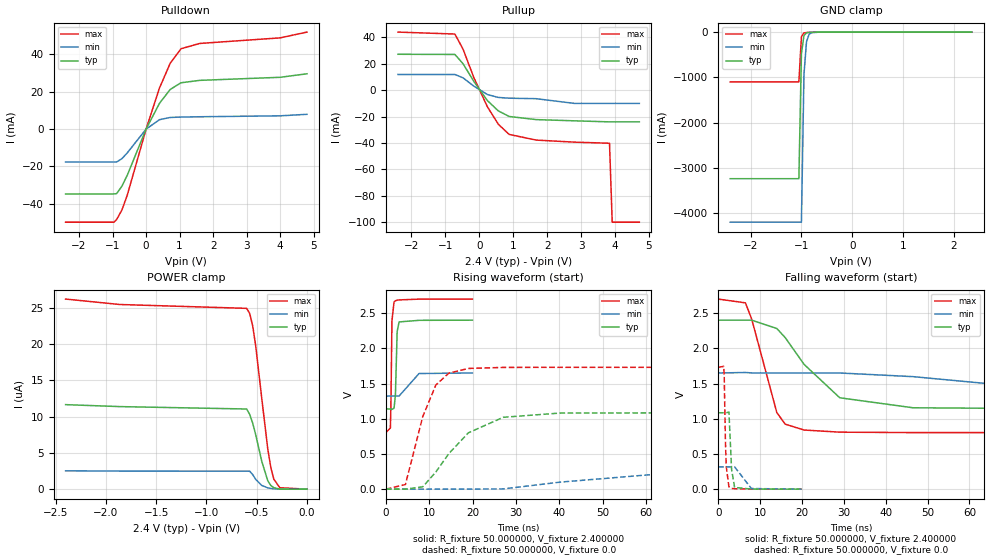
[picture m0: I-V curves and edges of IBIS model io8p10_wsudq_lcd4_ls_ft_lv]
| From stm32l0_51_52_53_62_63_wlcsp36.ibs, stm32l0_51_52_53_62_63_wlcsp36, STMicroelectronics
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|   Model io8p10_wsudq_lcd4_ls_ft_lv
[Model]  io8p10_wsudq_lcd4_ls_ft_lv
Model_type I/O
Polarity   Non-Inverting
Enable   Active-Low
Vinl =   0.720000V
Vinh =   1.680000V
Vmeas =  1.200000V
Cref =   50.000000pF
Rref =   100.000000M
Vref =   0.0V
C_comp   3.178800pF   3.170000pF   3.206700pF
[Temperature Range]   25.000000   0.105000k   -40.000000
[Pullup Reference]   2.400000V   1.650000V   2.700000V
[Pulldown Reference]   0.0V   0.0V   0.0V
[POWER Clamp Reference]   2.400000V   1.650000V   2.700000V
[GND Clamp Reference]   0.0V   0.0V   0.0V
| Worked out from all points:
|   slope of the pulldown table from 0 to 0.36 V, typ, clamps not added: 28.5 ohm
|   slope of the pullup table from 0 to 0.36 V, typ, clamps not added: 32.2 ohm
|   GND clamp passes 1 mA (typ) near -0.64 V on its own axis
|   rising waveform, R_fixture 50.000000, V_fixture 2.400000: 20-80 % time 297ps typ, 642ps min, 211ps max; typ from 1.14 V to 2.4 V
|   rising waveform, R_fixture 50.000000, V_fixture 0.0: 20-80 % time 9.37ns typ, 24.7ns min, 4.83ns max; typ from 0 V to 1.08 V
|   falling waveform, R_fixture 50.000000, V_fixture 2.400000: 20-80 % time 10ns typ, 27ns min, 4.94ns max; typ from 2.4 V to 1.14 V
|   falling waveform, R_fixture 50.000000, V_fixture 0.0: 20-80 % time 491ps typ, 860ps min, 390ps max; typ from 1.08 V to 0 V
[Pulldown]
|Voltage   I(typ)   I(min)   I(max)
-2.4V     -34.7mA    -17.61mA   -49.82mA
-960mV    -34.7mA    -17.61mA   -49.82mA
-880mV    -34.55mA   -17.61mA   -48.46mA
-720mV    -30.52mA   -15.79mA   -43.28mA
-560mV    -24.65mA   -12.68mA   -35.33mA
0V        326fA      0A         140fA
400mV     13.84mA    5.066mA    22.03mA
720mV     21.25mA    6.254mA    35.26mA
1.04V     24.82mA    6.464mA    43.03mA
1.6V      26.11mA    6.627mA    45.88mA
4V        27.76mA    7.125mA    48.87mA
4.8V      29.64mA    7.94mA     51.96mA
[Pullup]
|Voltage   I(typ)   I(min)   I(max)
-2.4V     27.21mA    11.89mA    44.01mA
-720mV    27.06mA    11.89mA    42.53mA
-480mV    20.06mA    9.352mA    31.11mA
-160mV    6.586mA    3.048mA    9.467mA
240mV     -7.917mA   -3.299mA   -12.65mA
560mV     -15.67mA   -5.497mA   -25.76mA
880mV     -19.92mA   -6.062mA   -33.51mA
1.68V     -22.29mA   -6.449mA   -37.81mA
2.8V      -23.2mA    -10mA      -39.35mA
3.84V     -24mA      -10mA      -40.2mA
3.92V     -24mA      -10mA      -100mA
4.72V     -24mA      -10mA      -100mA
[GND_clamp]
|Voltage   I(typ)   I(min)   I(max)
-2.4V     -3.238A    -4.199A    -1.101A
-1.05V    -3.238A    -4.199A    -1.101A
-1V       -476.5mA   -4.199A    -104.7mA
-950mV    -76.68mA   -936.1mA   -18.74mA
-900mV    -16.85mA   -213.2mA   -9.358mA
-850mV    -6.706mA   -51.12mA   -6.778mA
-800mV    -4.108mA   -13.92mA   -4.995mA
-650mV    -1.07mA    -1.211mA   -1.175mA
2.35V     0A         0A         0A
[POWER_clamp]
|Voltage   I(typ)   I(min)   I(max)
-2.4V     11.64uA    2.527uA    26.18uA
-1.86V    11.37uA    2.49uA     25.43uA
-600mV    11.04uA    2.475uA    24.9uA
-570mV    10.3uA     2.473uA    24.21uA
-540mV    9.097uA    2.001uA    22.48uA
-510mV    7.497uA    1.351uA    19.73uA
-450mV    3.846uA    513.2nA    12.52uA
-390mV    1.155uA    176.1nA    5.528uA
-360mV    508.6nA    103.4nA    2.997uA
-330mV    204.7nA    61.05nA    1.375uA
-270mV    0A         0A         195.3nA
0V        0A         0A         0A
[Ramp]
| variable   typ   min   max
dV/dt_r  0.65070/9.35439n   0.18996/24.62876n   1.03800/4.82133n
dV/dt_f  0.75690/10.02279n   0.19674/26.98375n   1.13815/4.93097n
R_load = 50.000000
[Rising Waveform]
R_fixture= 50.000000
V_fixture= 2.400000
V_fixture_min= 1.650000
V_fixture_max= 2.700000
|time   V(typ)   V(min)   V(max)
0s        1.139V     1.322V     803.1mV
1.041ns   1.138V     1.322V     868.6mV
1.161ns   1.137V     1.322V     1.178V
1.401ns   1.134V     1.322V     2.391V
1.882ns   1.148V     1.322V     2.658V
2.202ns   1.335V     1.322V     2.676V
2.603ns   2.24V      1.322V     2.684V
3.043ns   2.375V     1.322V     2.688V
7.648ns   2.398V     1.642V     2.699V
19.94ns   2.4V       1.65V      2.7V
[Rising Waveform]
R_fixture= 50.000000
V_fixture= 0.0
V_fixture_min= 0.0
V_fixture_max= 0.0
|time   V(typ)   V(min)   V(max)
0s        -626.8nV   -3.014uV   -474.6nV
4.505ns   -926.4uV   97.79uV    64.76mV
8.509ns   32.85mV    -982uV     1.031V
11.51ns   242.5mV    -199.4uV   1.478V
14.51ns   504.5mV    -200.8uV   1.648V
19.02ns   799.7mV    -139.3uV   1.714V
27.03ns   1.02V      2.517mV    1.729V
40.04ns   1.08V      98.31mV    1.73V
80.08ns   1.085V     302.3mV    1.73V
249.2ns   1.085V     316.6mV    1.73V
[Falling Waveform]
R_fixture= 50.000000
V_fixture= 2.400000
V_fixture_min= 1.650000
V_fixture_max= 2.700000
|time   V(typ)   V(min)   V(max)
0s        2.4V       1.65V      2.7V
6.507ns   2.401V     1.657V     2.646V
8.008ns   2.4V       1.651V     2.415V
14.01ns   2.282V     1.65V      1.086V
16.02ns   2.151V     1.65V      923.1mV
20.52ns   1.772V     1.65V      839.8mV
29.03ns   1.298V     1.65V      809.7mV
46.55ns   1.156V     1.598V     803.4mV
91.09ns   1.139V     1.35V      803.1mV
249.2ns   1.139V     1.322V     803.1mV
[Falling Waveform]
R_fixture= 50.000000
V_fixture= 0.0
V_fixture_min= 0.0
V_fixture_max= 0.0
|time   V(typ)   V(min)   V(max)
0s        1.085V     316.6mV    1.73V
1.321ns   1.085V     316.6mV    1.744V
1.441ns   1.085V     316.6mV    1.592V
1.722ns   1.084V     316.6mV    697.3mV
1.922ns   1.084V     316.6mV    322.5mV
2.563ns   1.096V     316.6mV    33.34mV
3.203ns   277.1mV    316.4mV    10.4mV
3.924ns   24.67mV    316.3mV    5.923mV
7.928ns   1.392mV    9.009mV    1.414mV
19.94ns   -626.8nV   -3.014uV   -474.6nV
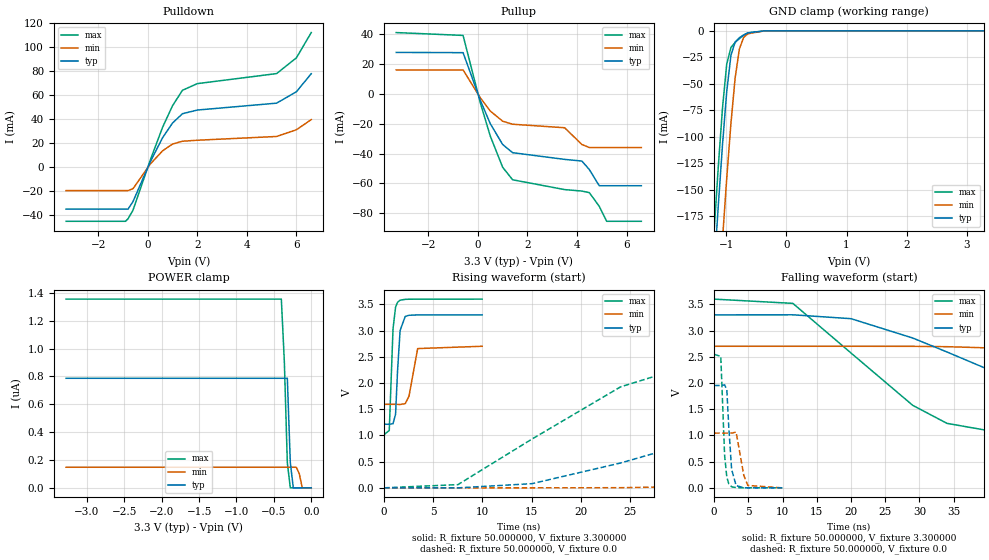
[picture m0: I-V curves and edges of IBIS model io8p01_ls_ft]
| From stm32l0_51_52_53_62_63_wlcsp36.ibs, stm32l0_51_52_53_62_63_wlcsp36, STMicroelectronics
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|   Model io8p01_ls_ft
[Model]  io8p01_ls_ft
Model_type I/O
Polarity   Non-Inverting
Enable   Active-Low
Vinl =   0.990000V
Vinh =   2.310000V
Vmeas =  1.650000V
Cref =   50.000000pF
Rref =   100.000000M
Vref =   0.0V
C_comp   4.606100pF   4.563500pF   4.706200pF
[Temperature Range]   25.000000   0.125000k   -40.000000
[Pullup Reference]   3.300000V   2.700000V   3.600000V
[Pulldown Reference]   0.0V   0.0V   0.0V
[POWER Clamp Reference]   3.300000V   2.700000V   3.600000V
[GND Clamp Reference]   0.0V   0.0V   0.0V
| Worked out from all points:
|   slope of the pulldown table from 0 to 0.495 V, typ, clamps not added: 23.6 ohm
|   slope of the pullup table from 0 to 0.495 V, typ, clamps not added: 24.9 ohm
|   GND clamp passes 1 mA (typ) near -0.59 V on its own axis
|   rising waveform, R_fixture 50.000000, V_fixture 3.300000: 20-80 % time 317ps typ, 427ps min, 299ps max; typ from 1.21 V to 3.3 V
|   rising waveform, R_fixture 50.000000, V_fixture 0.0: 20-80 % time 27.1ns typ, 59.6ns min, 13.7ns max; typ from 0 V to 1.95 V
|   falling waveform, R_fixture 50.000000, V_fixture 3.300000: 20-80 % time 24.6ns typ, 53.4ns min, 13.5ns max; typ from 3.3 V to 1.21 V
|   falling waveform, R_fixture 50.000000, V_fixture 0.0: 20-80 % time 521ps typ, 684ps min, 457ps max; typ from 1.95 V to 0 V
[Pulldown]
|Voltage   I(typ)   I(min)   I(max)
-3.3V     -34.78mA   -19.34mA   -44.89mA
-900mV    -34.78mA   -19.34mA   -44.89mA
-800mV    -34.78mA   -19.34mA   -42.84mA
-600mV    -28.56mA   -17.8mA    -35.75mA
100mV     4.638mA    2.744mA    6.076mA
600mV     24.8mA     13.84mA    33.52mA
1V        36.93mA    19.39mA    51.35mA
1.4V      44.67mA    21.76mA    64.17mA
2V        47.71mA    22.58mA    69.7mA
5.2V      53.44mA    25.71mA    78.05mA
6V        62.9mA     31.28mA    91.14mA
6.6V      77.96mA    39.76mA    112.2mA
[Pullup]
|Voltage   I(typ)   I(min)   I(max)
-3.3V     27.9mA     16.14mA    41.23mA
-600mV    27.74mA    16.14mA    39.31mA
100mV     -4.445mA   -2.663mA   -6.169mA
500mV     -20.02mA   -11.5mA    -28.37mA
1V        -33.98mA   -18.31mA   -49.27mA
1.4V      -39.45mA   -20.34mA   -57.65mA
3.5V      -43.95mA   -22.7mA    -64.24mA
4.2V      -45.08mA   -33.97mA   -65.24mA
4.5V      -50.83mA   -35.99mA   -66.3mA
4.9V      -61.64mA   -35.99mA   -75.5mA
5.2V      -61.64mA   -35.99mA   -85.54mA
6.6V      -61.64mA   -35.99mA   -85.54mA
[GND_clamp]
|Voltage   I(typ)   I(min)   I(max)
-3.3V     -2.276A    -2.356A    -2.25A
-1.2V     -226mA     -318.7mA   -189.2mA
-1.13V    -164.9mA   -256.6mA   -128.3mA
-1.06V    -107.5mA   -196.5mA   -72.78mA
-990mV    -57.32mA   -139.4mA   -31.39mA
-920mV    -23.22mA   -87.32mA   -15.73mA
-850mV    -10.58mA   -44.45mA   -10.94mA
-780mV    -6.539mA   -17.25mA   -7.356mA
-710mV    -3.933mA   -6.349mA   -4.308mA
-640mV    -1.955mA   -2.79mA    -1.975mA
-360mV    -2.06uA    -16.21uA   -459.5nA
3.28V     0A         0A         0A
[POWER_clamp]
|Voltage   I(typ)   I(min)   I(max)
-3.28V    786.7nA    148nA      1.355uA
-400mV    786.7nA    148nA      1.355uA
-360mV    786.7nA    148nA      908.2nA
-320mV    786.7nA    148nA      180.5nA
-280mV    182.6nA    148nA      0A
-240mV    0A         148nA      0A
-200mV    0A         148nA      0A
-160mV    0A         101.6nA    0A
-120mV    0A         0A         0A
0V        0A         0A         0A
[Ramp]
| variable   typ   min   max
dV/dt_r  1.17105/27.02437n   0.62495/59.40260n   1.52766/13.65025n
dV/dt_f  1.25166/24.62457n   0.65856/53.28008n   1.55292/13.51738n
R_load = 50.000000
[Rising Waveform]
R_fixture= 50.000000
V_fixture= 3.300000
V_fixture_min= 2.700000
V_fixture_max= 3.600000
|time   V(typ)   V(min)   V(max)
0s        1.214V     1.593V     1.012V
540.5ps   1.212V     1.593V     1.095V
920.9ps   1.223V     1.593V     3.034V
1.181ns   1.405V     1.593V     3.447V
1.381ns   2.232V     1.592V     3.539V
1.642ns   3.002V     1.589V     3.579V
2.162ns   3.269V     1.607V     3.595V
2.543ns   3.291V     1.748V     3.597V
3.423ns   3.298V     2.656V     3.598V
9.97ns    3.299V     2.7V       3.599V
[Rising Waveform]
R_fixture= 50.000000
V_fixture= 0.0
V_fixture_min= 0.0
V_fixture_max= 0.0
|time   V(typ)   V(min)   V(max)
0s        202uV      74.24uV    386.7uV
7.508ns   -454.6uV   -170.3uV   60.99mV
15.02ns   79.23mV    -153.8uV   929.1mV
24.02ns   473.2mV    2.685mV    1.925V
30.53ns   824.5mV    23.25mV    2.304V
38.04ns   1.181V     67.13mV    2.465V
54.55ns   1.671V     242mV      2.535V
75.58ns   1.884V     510.7mV    2.545V
137.6ns   1.951V     949.9mV    2.546V
249.2ns   1.952V     1.044V     2.546V
[Falling Waveform]
R_fixture= 50.000000
V_fixture= 3.300000
V_fixture_min= 2.700000
V_fixture_max= 3.600000
|time   V(typ)   V(min)   V(max)
0s        3.299V     2.7V       3.599V
11.51ns   3.3V       2.7V       3.518V
20.02ns   3.226V     2.7V       2.57V
29.03ns   2.857V     2.699V     1.573V
34.03ns   2.591V     2.692V     1.23V
39.54ns   2.287V     2.671V     1.104V
56.06ns   1.536V     2.532V     1.032V
72.07ns   1.323V     2.323V     1.018V
127.1ns   1.223V     1.744V     1.012V
249.2ns   1.214V     1.593V     1.012V
[Falling Waveform]
R_fixture= 50.000000
V_fixture= 0.0
V_fixture_min= 0.0
V_fixture_max= 0.0
|time   V(typ)   V(min)   V(max)
0s        1.952V     1.044V     2.546V
981ps     1.952V     1.044V     2.508V
1.542ns   1.964V     1.044V     612.6mV
1.862ns   1.869V     1.044V     203.4mV
2.142ns   1.173V     1.044V     78.85mV
2.563ns   352.1mV    1.044V     20.32mV
3.223ns   42.58mV    1.065V     4.488mV
4.344ns   2.458mV    238.1mV    1.881mV
4.925ns   1.266mV    46.15mV    1.466mV
9.97ns    202uV      74.24uV    386.7uV
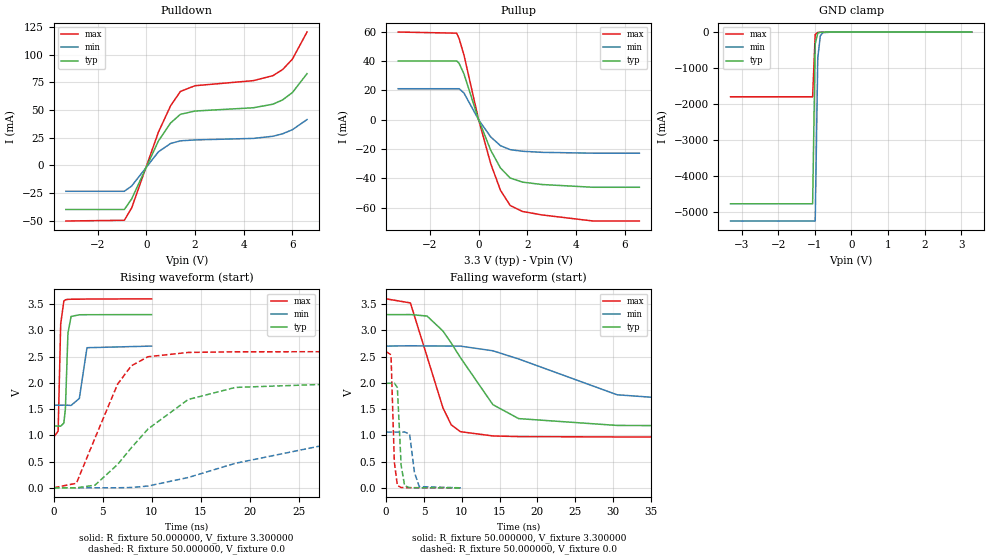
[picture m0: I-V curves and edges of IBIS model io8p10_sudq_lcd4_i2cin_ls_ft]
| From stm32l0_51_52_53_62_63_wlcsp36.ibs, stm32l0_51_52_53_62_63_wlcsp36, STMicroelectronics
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|   Model io8p10_sudq_lcd4_i2cin_ls_ft
[Model]  io8p10_sudq_lcd4_i2cin_ls_ft
Model_type I/O
Polarity   Non-Inverting
Enable   Active-Low
Vinl =   0.990000V
Vinh =   2.310000V
Vmeas =  1.650000V
Cref =   50.000000pF
Rref =   100.000000M
Vref =   0.0V
C_comp   2.499500pF   2.460800pF   2.557800pF
[Temperature Range]   25.000000   0.125000k   -40.000000
[Pullup Reference]   3.300000V   2.700000V   3.600000V
[Pulldown Reference]   0.0V   0.0V   0.0V
[POWER Clamp Reference]   3.300000V   2.700000V   3.600000V
[GND Clamp Reference]   0.0V   0.0V   0.0V
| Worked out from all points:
|   slope of the pulldown table from 0 to 0.495 V, typ, clamps not added: 22.6 ohm
|   slope of the pullup table from 0 to 0.495 V, typ, clamps not added: 23.9 ohm
|   GND clamp passes 1 mA (typ) near -0.64 V on its own axis
|   rising waveform, R_fixture 50.000000, V_fixture 3.300000: 20-80 % time 216ps typ, 363ps min, 176ps max; typ from 1.18 V to 3.3 V
|   rising waveform, R_fixture 50.000000, V_fixture 0.0: 20-80 % time 6.51ns typ, 13.6ns min, 3.46ns max; typ from 0 V to 1.99 V
|   falling waveform, R_fixture 50.000000, V_fixture 3.300000: 20-80 % time 5.95ns typ, 12.6ns min, 3.26ns max; typ from 3.3 V to 1.18 V
|   falling waveform, R_fixture 50.000000, V_fixture 0.0: 20-80 % time 383ps typ, 552ps min, 306ps max; typ from 1.99 V to 0 V
[Pulldown]
|Voltage   I(typ)   I(min)   I(max)
-3.3V     -39.83mA   -23.37mA   -50.2mA
-900mV    -39.83mA   -23.37mA   -49.53mA
-600mV    -30.28mA   -18.59mA   -38.45mA
500mV     22.11mA    12.28mA    30.1mA
1V        38.33mA    19.81mA    53.88mA
1.4V      46.1mA     22.18mA    66.72mA
2V        49.07mA    23.01mA    71.93mA
4.4V      52.05mA    24.38mA    76.53mA
5.2V      55.25mA    26.3mA     81.02mA
5.6V      59.18mA    28.57mA    86.57mA
6V        65.78mA    32.24mA    95.96mA
6.6V      82.83mA    41.41mA    120.4mA
[Pullup]
|Voltage   I(typ)   I(min)   I(max)
-3.3V     40.03mA    21.09mA    59.71mA
-900mV    40.03mA    21.09mA    58.93mA
-800mV    38.38mA    21.09mA    55.25mA
-600mV    31.19mA    18.17mA    44.03mA
0V        90fA       25.2pA     0A
500mV     -20.88mA   -11.78mA   -30.07mA
900mV     -32.92mA   -17.72mA   -48.15mA
1.3V      -39.75mA   -20.41mA   -58.47mA
1.8V      -42.5mA    -21.48mA   -62.49mA
2.6V      -44.14mA   -22.23mA   -64.85mA
4.7V      -46.01mA   -22.8mA    -69mA
6.6V      -46.01mA   -22.8mA    -69mA
[GND_clamp]
|Voltage   I(typ)   I(min)   I(max)
-3.3V     -4.766A    -5.244A    -1.797A
-1.06V    -4.766A    -5.244A    -1.797A
-990mV    -326.4mA   -5.244A    -67.85mA
-920mV    -28.83mA   -721.7mA   -11.08mA
-850mV    -6.686mA   -104.1mA   -6.707mA
-780mV    -3.552mA   -17.28mA   -4.326mA
-500mV    -59.41uA   -172uA     -34.91uA
3.28V     0A         0A         0A
[POWER_clamp]
|Voltage   I(typ)   I(min)   I(max)
-3.28V    0A         0A         0A
0V        0A         0A         0A
[Ramp]
| variable   typ   min   max
dV/dt_r  1.19502/6.49677n   0.62940/13.54579n   1.55568/3.45802n
dV/dt_f  1.27374/5.93801n   0.65346/12.50423n   1.57856/3.25817n
R_load = 50.000000
[Rising Waveform]
R_fixture= 50.000000
V_fixture= 3.300000
V_fixture_min= 2.700000
V_fixture_max= 3.600000
|time   V(typ)   V(min)   V(max)
0s        1.177V     1.573V     969mV
440.4ps   1.176V     1.573V     1.079V
700.7ps   1.173V     1.573V     3.119V
1.021ns   1.232V     1.574V     3.558V
1.181ns   1.501V     1.574V     3.582V
1.441ns   2.946V     1.572V     3.591V
1.762ns   3.265V     1.569V     3.593V
2.603ns   3.297V     1.702V     3.594V
3.383ns   3.298V     2.669V     3.597V
9.97ns    3.3V       2.7V       3.6V
[Rising Waveform]
R_fixture= 50.000000
V_fixture= 0.0
V_fixture_min= 0.0
V_fixture_max= 0.0
|time   V(typ)   V(min)   V(max)
0s        -91.98nV   -5.808uV   366.1uV
2.302ns   -2.088mV   -1.67mV    84.83mV
4.204ns   49.92mV    -877.6uV   947.8mV
6.507ns   443.7mV    -597.1uV   1.975V
7.908ns   761.3mV    4.472mV    2.324V
9.61ns    1.12V      32.53mV    2.497V
13.71ns   1.682V     195mV      2.579V
18.52ns   1.912V     465.8mV    2.591V
30.23ns   1.988V     911.7mV    2.593V
49.85ns   1.992V     1.062V     2.593V
[Falling Waveform]
R_fixture= 50.000000
V_fixture= 3.300000
V_fixture_min= 2.700000
V_fixture_max= 3.600000
|time   V(typ)   V(min)   V(max)
0s        3.3V       2.7V       3.6V
3.203ns   3.301V     2.707V     3.523V
5.405ns   3.273V     2.703V     2.502V
7.508ns   2.988V     2.702V     1.524V
8.609ns   2.757V     2.701V     1.2V
9.81ns    2.483V     2.7V       1.07V
14.11ns   1.585V     2.611V     988.7mV
17.52ns   1.319V     2.455V     976.3mV
30.53ns   1.189V     1.773V     969.3mV
49.85ns   1.177V     1.573V     969mV
[Falling Waveform]
R_fixture= 50.000000
V_fixture= 0.0
V_fixture_min= 0.0
V_fixture_max= 0.0
|time   V(typ)   V(min)   V(max)
0s        1.992V     1.062V     2.593V
640.6ps   1.992V     1.062V     2.536V
1.081ns   1.996V     1.062V     494mV
1.481ns   1.911V     1.062V     46.2mV
1.982ns   427.2mV    1.061V     6.117mV
2.442ns   40.65mV    1.065V     3.807mV
3.103ns   3.239mV    1.021V     3.289mV
3.744ns   1.612mV    289.6mV    3.365mV
4.384ns   1.274mV    23.4mV     2.171mV
9.97ns    -91.98nV   -5.808uV   366.1uV
